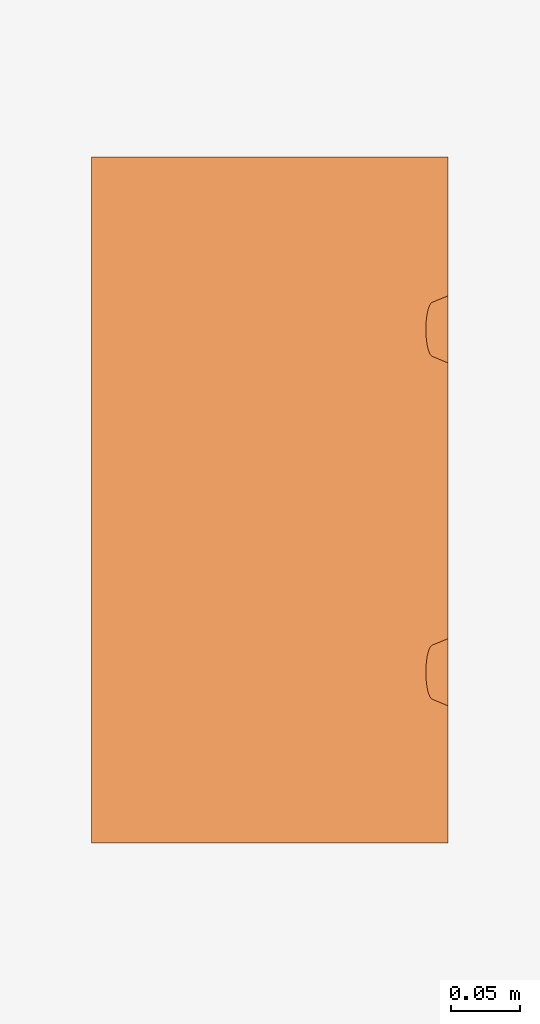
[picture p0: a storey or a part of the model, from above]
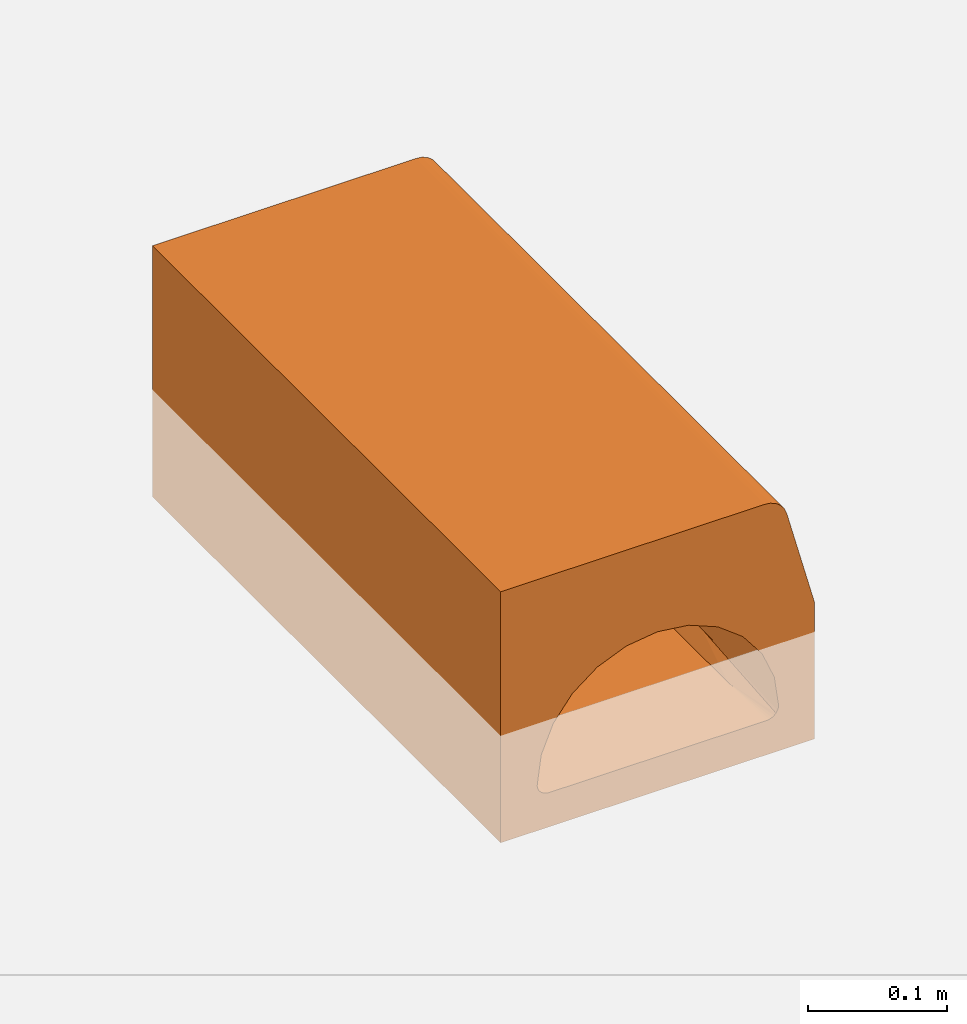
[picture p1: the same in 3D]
Properties of the parts of a building model (IFC2X3)

# File
Description: ViewDefinition [CoordinationView]
File name: T0127 - Channel - 500mm LG - 220mm High.ifc
Time: 2013-09-04T09:01:08
Written by: Autodesk Revit 2013
Made in: 20120221_2030(x64)

# IfcProject, Project Number
LongName: Project Name; Phase: Project Status

# IfcSite, Default
RefLatitude: 42, 21, 30, 344238; RefLongitude: -71, -3, -35, -194702; RefElevation: 0 mm

# IfcBuilding
Pset_BuildingCommon - NumberOfStoreys: 1
Other - Project Number: Project Number; Project Name: Project Name; Client Name: Owner; Project Address: ## Street City, State Zip; Project Status: Project Status; Project Issue Date: Issue Date

# IfcBuildingStorey, Level 1
LongName: Level 1; Elevation: 0 mm
Constraints - Elevation Base: 0; Elevation: 0 mm
Graphics - Line Pattern: Center; Color: 0; Symbol: M_Level Head - Circle: M_Level Head - Circle; Symbol at End 1 Default: no; Symbol at End 2 Default: yes; Line Weight: 1
Identity Data - Name: Level 1; Building Story: yes; Structural: no
Dimensions - Computation Height: 0 mm

# IfcBuildingElementProxy: T0127 - Channel - 500mm LG - 220mm High, Civil-Drainage-Channel-ACO-KerbDrain-KD200:T0127 - Channel - 500mm LG - 220mm High:T0127 - Channel - 500mm LG - 220mm High:308203
In: Level 1
Material: ACO Polymer Concrete.
Dimensions - Volume: 18468519 mm3; Void length: 500 mm; Void Depth.: -95 mm
Constraints - Moves With Nearby Elements: no; Level: Level: Level 1
Phasing - Phase Created: New Construction
Pset_BuildingElementProxyCommon - Reference: T0127 - Channel - 500mm LG - 220mm High
General - TagNumber: 0.000000; SerialNumber: 0.000000
Other - CreatedBy: www.aco.co.uk; Revision: 1
Identity Data - Assembly Code: D2040; OmniClass Number: 23.70.50.24; Fax: +44 (0)1462 815895; Model: ACO KerbDrain KD200; Manufacturer: ACO Technologies plc - ACO Water Management Division; Cost: 0; Type Comments: ACO KerbDrain KD200 half battered kerb unit 220 high 500mm long; OmniClass Title: Rainwater Removal; Telephone: +44 (0)1462 816666; Address: ACO Business Park, Hitchin Road, Shefford, Bedfordshire, United Kingdom SG17 5TE; Product Page URL: http://www.aco.co.uk/product_detail.php?id=3; URL: www.aco.co.uk; Product brochure: http://www.aco.co.uk/download.php?id=120; e-mail Sales: customersupport@aco.co.uk; Model Description: Combined kerb and drainage system; Price: POA - contact ACO; Product Code: T0127; Installation guidelines: http://www.aco.co.uk/download.php?id=120; e-mail Technical: technical@aco.co.uk; Maintenance guidelines: http://www.aco.co.uk/download.php?id=120; Assembly Description: Rain Water Drainage
Construction - Channelunit_235: no; Blindunit_220: no; Channelunit_220: yes; Access Cover: no; Accessunit_235: no; Accessunit_220: no; Closing end cap: no; Blindunit_235: no
Data - Installation - Concrete Grade: Refer to brochure; ACO Hydraulic Design Software: http://www.acodesign.co.uk; Drainage Slot Intake area: 14592mm²/m; Channel C.S.A: 0.02m²; Invert Depth: 190mm; Hydraulic Performance: http://www.aco.co.uk/download.php?id=120; Drainage Slot Width: 50mm; Product Dimensions: 500mm x 260mm x 220mm (LxWxH); Concrete Surround Volume - Load Class A 15 - D 400 - Concrete Pavement: 0.20m³/m; Product Standard: BS EN 1433:2002, CE marked, Kitemarked; Load Class: A 15 - D 400 A 15 - D 400; Product Weight: 39.7 Kg
Materials and Finishes - Access Cover/Frame Finish: N/A; Channel Colour: Grey; End Cap Colour: N/A; End Cap Material: N/A; Access Cover/Frame Colour: N/A; Channel Material: Vienite® Synthetic Resin Concrete; Access Cover/Frame Material: N/A
Green Building Properties - End Cap Recycled Material Content: N/A; Channel Recyclable: Fully recyclable; Access Cover/Frame Recycled Material Content: N/A; End Cap Recyclable: N/A; Channel Recycled Material Content: 20% minimum; Access Cover/Frame Recyclable: N/A

# IfcOpeningElement: Recess
In: Level 1
Dimensions - Thickness: 400 mm; Perimeter: 51360 mm; Area: 151470000 mm2; Volume: 60575650000 mm3
Structural - Enable Analytical Model: no; Structural: no
Constraints - Level: Level: Level 1; Related to Mass: no; Room Bounding: yes; Height Offset From Level: 0 mm
Phasing - Phase Created: New Construction
Analytical Properties - Roughness: 1; Absorptance: 0.1
Construction - Function: 0; Default Thickness: 400 mm
Graphics - Coarse Scale Fill Color: 0
Materials and Finishes - Structural Material: Plant

# IfcSlab: Floor:Generic Floor - 400mm, Floor:Generic Floor - 400mm:193825
In: Level 1
PredefinedType: FLOOR; Material: Plant 400 mm
Dimensions - Thickness: 400 mm; Perimeter: 51360 mm; Area: 151470000 mm2; Volume: 60575650000 mm3
Structural - Enable Analytical Model: no; Structural: no
Constraints - Level: Level: Level 1; Related to Mass: no; Room Bounding: yes; Height Offset From Level: 0 mm
Phasing - Phase Created: New Construction
Pset_SlabCommon - Reference: Generic Floor - 400mm; IsExternal: no; LoadBearing: yes
Analytical Properties - Roughness: 1; Absorptance: 0.1
Construction - Function: 0; Default Thickness: 400 mm
Graphics - Coarse Scale Fill Color: 0
Materials and Finishes - Structural Material: Plant
